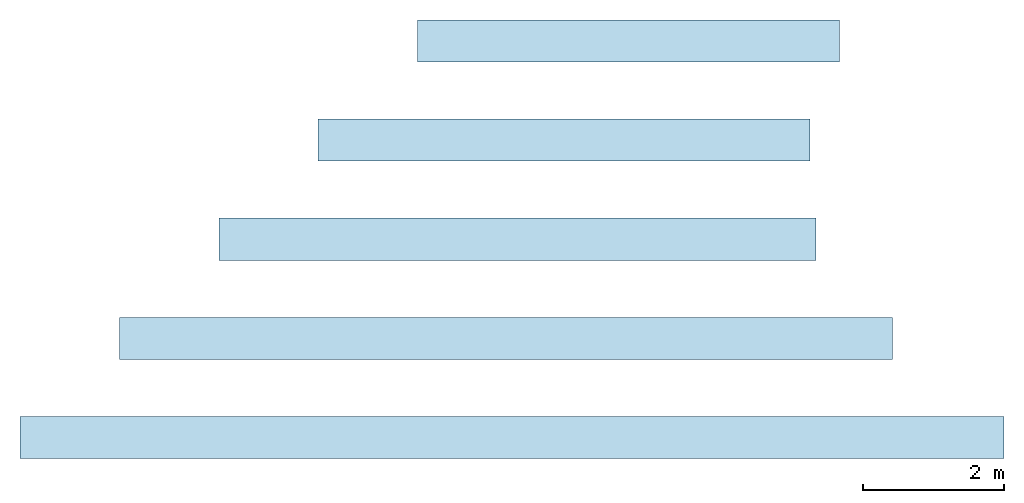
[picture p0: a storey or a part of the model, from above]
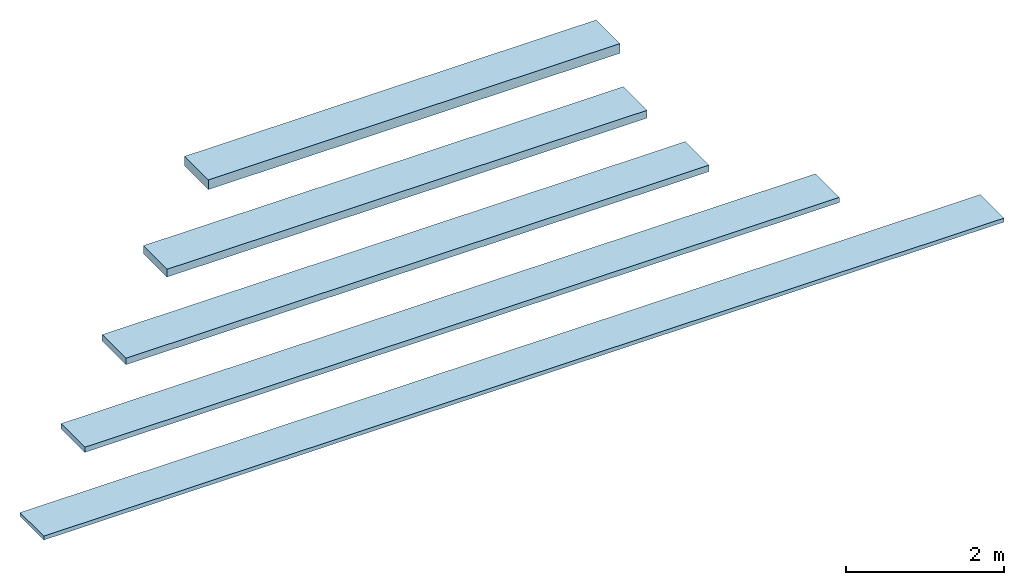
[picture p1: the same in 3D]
Properties of the parts of a building model (IFC2X3)

# File
Description: ViewDefinition [CoordinationView_V2.0, QuantityTakeOffAddOnView]
Time: 2021-05-19T20:20:11
Written by: The EXPRESS Data Manager Version 5.02.0100.07 : 28 Aug 2013
Made in: 20190108_1515(x64) - Exporter 19.1.0.0 - Alternate UI 19.1.0.0
Comment: STEP Physical File produced by: The EXPRESS Data Manager Version 5.02.0100.07 : 28 Aug 2013 * Module: EDMstepFileFactory/EDMstandAlone * Creation date: Wed May 19 20:20:11 2021 * Host: lt-026 * Database: C:\Users\WF2BF~1.POE\AppData\Local\Temp\{480D5C36-97AD-4BCC-B42C-12BA28B0F3CB}\ifc * Database version: 5507 * Database creation date: Wed May 19 20:20:10 2021 * Schema: IFC2X3 * Model: DataRepository.ifc * Model creation date: Wed May 19 20:20:10 2021 * Header model: DataRepository.ifc_HeaderModel * Header model creation date: Wed May 19 20:20:10 2021 * EDMuser: sdai-user * EDMgroup: sdai-group * License ID and type: 5605 : Permanent license. Expiry date: * EDMstepFileFactory options: 020000

# IfcSite, Default
RefLatitude: 42, 24, 53, 508911; RefLongitude: -71, -15, -29, -58837; RefElevation: 0 mm
Other - Category: Project Information

# IfcBuilding
Pset_BuildingCommon - NumberOfStoreys: 1
Pset_ProductRequirements - Category: Project Information; sets with these values: 2

# IfcBuildingStorey: Level:Level 1, Level 1
LongName: Level 1; Elevation: 0 mm
Pset_AirSideSystemInformation - Name: Level 1
Pset_ProductRequirements - Name: Level 1; Category: Levels
Constraints - Elevation: 0 mm
Dimensions - Computation Height: 0 mm
Identity Data - Building Story: yes; Name: Level 1; Structural: no
Other - Category: Levels; Family: Level: Level 1; Family and Type: Level: Level 1; Type: Level: Level 1; Type Id: Level: Level 1
Constraints(Type) - Elevation Base: Project Base Point
Graphics(Type) - Color: 0; Line Pattern: Solid; Line Weight: 1; Symbol at End 1 Default: no; Symbol at End 2 Default: yes
Identity Data(Type) - Type Name: Level 1
Other(Type) - Category: Levels; Family Name: Level

# IfcRoof: Basic Roof:NLRS_27_RO_TR 312_100x600x8500mm, Basic Roof:NLRS_27_RO_TR 312_100x600x8500mm:2467
In: Level 1
Classification: 27 Daken (Uniformat)
Pset_ElementShading - Roughness: 304.8 mm
Pset_ManufacturerTypeInformation - Manufacturer: Knauf Insulation B.V.
Pset_ProductRequirements - Category: Roofs
Pset_QuantityTakeOff - Reference: NLRS_27_RO_TR 312_100x600x8500mm
Pset_RoofCommon - IsExternal: yes; Reference: NLRS_27_RO_TR 312_100x600x8500mm; ProjectedArea: 5.1 m2; TotalArea: 5.1 m2
Constraints - Base Level: Level: Level 1; Base Offset From Level: 0 mm; Cutoff Offset: 0 mm; Related to Mass: no; Room Bounding: yes
Construction - Fascia Depth: 0 mm; Rafter Cut: Plumb Cut; Maximum Ridge Height: 100 mm
Dimensions - Area: 5.1 m2; Thickness: 100 mm; Volume: 0.51 m3
Other - Category: Roofs; Family: Basic Roof: NLRS_27_RO_TR 312_100x600x8500mm; Family and Type: Basic Roof: NLRS_27_RO_TR 312_100x600x8500mm; Type: Basic Roof: NLRS_27_RO_TR 312_100x600x8500mm; Type Id: Basic Roof: NLRS_27_RO_TR 312_100x600x8500mm
Phasing - Phase Created: New Construction
Analytical Properties(Type) - Roughness: 1; Thermal mass: 0; Absorptance: 0.1; Heat Transfer Coefficient (U): 0.4; Thermal Resistance (R): 2.5
Construction(Type) - Default Thickness: 100 mm
Graphics(Type) - Coarse Scale Fill Color: 0
Identity Data(Type) - Type Image: Raster image: TR 312 .jpg (2); Assembly Code: 27; Assembly Description: Daken; Description: TR 312 - 100mm; Manufacturer: Knauf Insulation B.V.; Model: TR312 is een glaswoldeken met alukraftbkleding en ECOSE® Technology; Type Name: NLRS_27_RO_TR 312_100x600x8500mm; URL: www.knaufinsulation.nl
Other(Type) - Category: Roofs; Family Name: Basic Roof

# IfcRoof: Basic Roof:NLRS_27_RO_TR 312_120x600x7000mm, Basic Roof:NLRS_27_RO_TR 312_120x600x7000mm:2476
In: Level 1
Classification: 27 Daken (Uniformat)
Pset_ElementShading - Roughness: 304.8 mm
Pset_ManufacturerTypeInformation - Manufacturer: Knauf Insulation B.V.
Pset_ProductRequirements - Category: Roofs
Pset_QuantityTakeOff - Reference: NLRS_27_RO_TR 312_120x600x7000mm
Pset_RoofCommon - IsExternal: yes; Reference: NLRS_27_RO_TR 312_120x600x7000mm; ProjectedArea: 4.2 m2; TotalArea: 4.2 m2
Constraints - Base Level: Level: Level 1; Base Offset From Level: 0 mm; Cutoff Offset: 0 mm; Related to Mass: no; Room Bounding: yes
Construction - Fascia Depth: 0 mm; Rafter Cut: Plumb Cut; Maximum Ridge Height: 120 mm
Dimensions - Area: 4.2 m2; Thickness: 120 mm; Volume: 0.504 m3
Other - Category: Roofs; Family: Basic Roof: NLRS_27_RO_TR 312_120x600x7000mm; Family and Type: Basic Roof: NLRS_27_RO_TR 312_120x600x7000mm; Type: Basic Roof: NLRS_27_RO_TR 312_120x600x7000mm; Type Id: Basic Roof: NLRS_27_RO_TR 312_120x600x7000mm
Phasing - Phase Created: New Construction
Analytical Properties(Type) - Roughness: 1; Thermal mass: 0; Absorptance: 0.1; Heat Transfer Coefficient (U): 0.333333; Thermal Resistance (R): 3
Construction(Type) - Default Thickness: 120 mm
Graphics(Type) - Coarse Scale Fill Color: 0
Identity Data(Type) - Type Image: Raster image: TR 312 .jpg (2); Assembly Code: 27; Assembly Description: Daken; Description: TR 312 - 120mm; Manufacturer: Knauf Insulation B.V.; Model: TR312 is een glaswoldeken met alukraftbkleding en ECOSE® Technology; Type Name: NLRS_27_RO_TR 312_120x600x7000mm; URL: www.knaufinsulation.nl
Other(Type) - Category: Roofs; Family Name: Basic Roof

# IfcRoof: Basic Roof:NLRS_27_RO_TR 312_150X600X6000mm, Basic Roof:NLRS_27_RO_TR 312_150X600X6000mm:2485
In: Level 1
Classification: 27 Daken (Uniformat)
Pset_ElementShading - Roughness: 304.8 mm
Pset_ManufacturerTypeInformation - Manufacturer: Knauf Insulation B.V.
Pset_ProductRequirements - Category: Roofs
Pset_QuantityTakeOff - Reference: NLRS_27_RO_TR 312_150X600X6000mm
Pset_RoofCommon - IsExternal: yes; Reference: NLRS_27_RO_TR 312_150X600X6000mm; ProjectedArea: 3.6 m2; TotalArea: 3.6 m2
Constraints - Base Level: Level: Level 1; Base Offset From Level: 0 mm; Cutoff Offset: 0 mm; Related to Mass: no; Room Bounding: yes
Construction - Fascia Depth: 0 mm; Rafter Cut: Plumb Cut; Maximum Ridge Height: 150 mm
Dimensions - Area: 3.6 m2; Thickness: 150 mm; Volume: 0.54 m3
Other - Category: Roofs; Family: Basic Roof: NLRS_27_RO_TR 312_150X600X6000mm; Family and Type: Basic Roof: NLRS_27_RO_TR 312_150X600X6000mm; Type: Basic Roof: NLRS_27_RO_TR 312_150X600X6000mm; Type Id: Basic Roof: NLRS_27_RO_TR 312_150X600X6000mm
Phasing - Phase Created: New Construction
Analytical Properties(Type) - Roughness: 1; Thermal mass: 0; Absorptance: 0.1; Heat Transfer Coefficient (U): 0.266667; Thermal Resistance (R): 3.75
Construction(Type) - Default Thickness: 150 mm
Graphics(Type) - Coarse Scale Fill Color: 0
Identity Data(Type) - Type Image: Raster image: TR 312 .jpg (2); Assembly Code: 27; Assembly Description: Daken; Description: TR 312 - 150mm; Manufacturer: Knauf Insulation B.V.; Model: TR312 is een glaswoldeken met alukraftbkleding en ECOSE® Technology; Type Name: NLRS_27_RO_TR 312_150X600X6000mm; URL: www.knaufinsulation.nl
Other(Type) - Category: Roofs; Family Name: Basic Roof

# IfcRoof: Basic Roof:NLRS_27_RO_TR 312_60x600x14000mm, Basic Roof:NLRS_27_RO_TR 312_60x600x14000mm:2449
In: Level 1
Classification: 27 Daken (Uniformat)
Pset_ElementShading - Roughness: 304.8 mm
Pset_ManufacturerTypeInformation - Manufacturer: Knauf Insulation B.V.
Pset_ProductRequirements - Category: Roofs
Pset_QuantityTakeOff - Reference: NLRS_27_RO_TR 312_60x600x14000mm
Pset_RoofCommon - Reference: NLRS_27_RO_TR 312_60x600x14000mm; IsExternal: yes; ProjectedArea: 8.4 m2; TotalArea: 8.4 m2
Constraints - Base Level: Level: Level 1; Base Offset From Level: 0 mm; Cutoff Offset: 0 mm; Related to Mass: no; Room Bounding: yes
Construction - Fascia Depth: 0 mm; Maximum Ridge Height: 60 mm; Rafter Cut: Plumb Cut
Dimensions - Area: 8.4 m2; Thickness: 60 mm; Volume: 0.504 m3
Other - Category: Roofs; Family: Basic Roof: NLRS_27_RO_TR 312_60x600x14000mm; Family and Type: Basic Roof: NLRS_27_RO_TR 312_60x600x14000mm; Type: Basic Roof: NLRS_27_RO_TR 312_60x600x14000mm; Type Id: Basic Roof: NLRS_27_RO_TR 312_60x600x14000mm
Phasing - Phase Created: New Construction
Analytical Properties(Type) - Absorptance: 0.1; Heat Transfer Coefficient (U): 0.666667; Roughness: 1; Thermal mass: 0; Thermal Resistance (R): 1.5
Construction(Type) - Default Thickness: 60 mm
Graphics(Type) - Coarse Scale Fill Color: 0
Identity Data(Type) - Assembly Code: 27; Assembly Description: Daken; Description: TR 312 - 60mm; Manufacturer: Knauf Insulation B.V.; Model: TR312 is een glaswoldeken met alukraftbkleding en ECOSE® Technology; Type Image: Raster image: TR 312 .jpg (2); Type Name: NLRS_27_RO_TR 312_60x600x14000mm; URL: www.knaufinsulation.nl
Other(Type) - Category: Roofs; Family Name: Basic Roof

# IfcRoof: Basic Roof:NLRS_27_RO_TR 312_80x600x11000mm, Basic Roof:NLRS_27_RO_TR 312_80x600x11000mm:2458
In: Level 1
Classification: 27 Daken (Uniformat)
Pset_ElementShading - Roughness: 304.8 mm
Pset_ManufacturerTypeInformation - Manufacturer: Knauf Insulation B.V.
Pset_ProductRequirements - Category: Roofs
Pset_QuantityTakeOff - Reference: NLRS_27_RO_TR 312_80x600x11000mm
Pset_RoofCommon - IsExternal: yes; Reference: NLRS_27_RO_TR 312_80x600x11000mm; ProjectedArea: 6.6 m2; TotalArea: 6.6 m2
Constraints - Base Level: Level: Level 1; Base Offset From Level: 0 mm; Cutoff Offset: 0 mm; Related to Mass: no; Room Bounding: yes
Construction - Fascia Depth: 0 mm; Rafter Cut: Plumb Cut; Maximum Ridge Height: 80 mm
Dimensions - Area: 6.6 m2; Thickness: 80 mm; Volume: 0.528 m3
Other - Category: Roofs; Family: Basic Roof: NLRS_27_RO_TR 312_80x600x11000mm; Family and Type: Basic Roof: NLRS_27_RO_TR 312_80x600x11000mm; Type: Basic Roof: NLRS_27_RO_TR 312_80x600x11000mm; Type Id: Basic Roof: NLRS_27_RO_TR 312_80x600x11000mm
Phasing - Phase Created: New Construction
Analytical Properties(Type) - Roughness: 1; Thermal mass: 0; Absorptance: 0.1; Heat Transfer Coefficient (U): 0.5; Thermal Resistance (R): 2
Construction(Type) - Default Thickness: 80 mm
Graphics(Type) - Coarse Scale Fill Color: 0
Identity Data(Type) - Type Image: Raster image: TR 312 .jpg (2); Assembly Code: 27; Assembly Description: Daken; Description: TR 312 - 80mm; Manufacturer: Knauf Insulation B.V.; Model: TR312 is een glaswoldeken met alukraftbkleding en ECOSE® Technology; Type Name: NLRS_27_RO_TR 312_80x600x11000mm; URL: www.knaufinsulation.nl
Other(Type) - Category: Roofs; Family Name: Basic Roof

# IfcSlab: Basic Roof:NLRS_27_RO_TR 312_100x600x8500mm, Basic Roof:NLRS_27_RO_TR 312_100x600x8500mm:2467
In: Level 1
PredefinedType: ROOF; Classification: 27 Daken (Uniformat); Material: Knauf Insulation_Ecose® glaswol TR 312 100 mm
Pset_ElementShading - Roughness: 304.8 mm
Pset_ManufacturerTypeInformation - Manufacturer: Knauf Insulation B.V.
Pset_ProductRequirements - Category: Roofs
Pset_QuantityTakeOff - Reference: NLRS_27_RO_TR 312_100x600x8500mm
Pset_ReinforcementBarPitchOfSlab - Description: TR 312 - 100mm; Reference: NLRS_27_RO_TR 312_100x600x8500mm
Pset_SlabCommon - IsExternal: yes; PitchAngle: 0 deg; Reference: NLRS_27_RO_TR 312_100x600x8500mm; ThermalTransmittance: 0.4 kg/K/s3
BaseQuantities - GrossArea: 0.473806 m2; NetArea: 12.02 m2; GrossVolume: 47.3806 m3; NetVolume: 0.51 m3; Perimeter: 18200 mm; Width: 100 mm

# IfcSlab: Basic Roof:NLRS_27_RO_TR 312_120x600x7000mm, Basic Roof:NLRS_27_RO_TR 312_120x600x7000mm:2476
In: Level 1
PredefinedType: ROOF; Classification: 27 Daken (Uniformat); Material: Knauf Insulation_Ecose® glaswol TR 312 120 mm
Pset_ElementShading - Roughness: 304.8 mm
Pset_ManufacturerTypeInformation - Manufacturer: Knauf Insulation B.V.
Pset_ProductRequirements - Category: Roofs
Pset_QuantityTakeOff - Reference: NLRS_27_RO_TR 312_120x600x7000mm
Pset_ReinforcementBarPitchOfSlab - Description: TR 312 - 120mm; Reference: NLRS_27_RO_TR 312_120x600x7000mm
Pset_SlabCommon - IsExternal: yes; PitchAngle: 0 deg; Reference: NLRS_27_RO_TR 312_120x600x7000mm; ThermalTransmittance: 0.333333 kg/K/s3
BaseQuantities - GrossArea: 0.390193 m2; NetArea: 10.224 m2; GrossVolume: 46.8231 m3; NetVolume: 0.504 m3; Perimeter: 15200 mm; Width: 120 mm

# IfcSlab: Basic Roof:NLRS_27_RO_TR 312_150X600X6000mm, Basic Roof:NLRS_27_RO_TR 312_150X600X6000mm:2485
In: Level 1
PredefinedType: ROOF; Classification: 27 Daken (Uniformat); Material: Knauf Insulation_Ecose® glaswol TR 312 150 mm
Pset_ElementShading - Roughness: 304.8 mm
Pset_ManufacturerTypeInformation - Manufacturer: Knauf Insulation B.V.
Pset_ProductRequirements - Category: Roofs
Pset_QuantityTakeOff - Reference: NLRS_27_RO_TR 312_150X600X6000mm
Pset_ReinforcementBarPitchOfSlab - Description: TR 312 - 150mm; Reference: NLRS_27_RO_TR 312_150X600X6000mm
Pset_SlabCommon - IsExternal: yes; PitchAngle: 0 deg; Reference: NLRS_27_RO_TR 312_150X600X6000mm; ThermalTransmittance: 0.266667 kg/K/s3
BaseQuantities - GrossArea: 0.334451 m2; NetArea: 9.18 m2; GrossVolume: 50.1676 m3; NetVolume: 0.54 m3; Perimeter: 13200 mm; Width: 150 mm

# IfcSlab: Basic Roof:NLRS_27_RO_TR 312_60x600x14000mm, Basic Roof:NLRS_27_RO_TR 312_60x600x14000mm:2449
In: Level 1
PredefinedType: ROOF; Classification: 27 Daken (Uniformat); Material: Knauf Insulation_Ecose® glaswol TR 312 60 mm
Pset_ElementShading - Roughness: 304.8 mm
Pset_ManufacturerTypeInformation - Manufacturer: Knauf Insulation B.V.
Pset_ProductRequirements - Category: Roofs
Pset_QuantityTakeOff - Reference: NLRS_27_RO_TR 312_60x600x14000mm
Pset_ReinforcementBarPitchOfSlab - Description: TR 312 - 60mm; Reference: NLRS_27_RO_TR 312_60x600x14000mm
Pset_SlabCommon - Reference: NLRS_27_RO_TR 312_60x600x14000mm; IsExternal: yes; ThermalTransmittance: 0.666667 kg/K/s3; PitchAngle: 0 deg
BaseQuantities - GrossArea: 0.780386 m2; NetArea: 18.552 m2; GrossVolume: 46.8231 m3; NetVolume: 0.504 m3; Perimeter: 29200 mm; Width: 60 mm

# IfcSlab: Basic Roof:NLRS_27_RO_TR 312_80x600x11000mm, Basic Roof:NLRS_27_RO_TR 312_80x600x11000mm:2458
In: Level 1
PredefinedType: ROOF; Classification: 27 Daken (Uniformat); Material: Knauf Insulation_Ecose® glaswol TR 312 80 mm
Pset_ElementShading - Roughness: 304.8 mm
Pset_ManufacturerTypeInformation - Manufacturer: Knauf Insulation B.V.
Pset_ProductRequirements - Category: Roofs
Pset_QuantityTakeOff - Reference: NLRS_27_RO_TR 312_80x600x11000mm
Pset_ReinforcementBarPitchOfSlab - Description: TR 312 - 80mm; Reference: NLRS_27_RO_TR 312_80x600x11000mm
Pset_SlabCommon - IsExternal: yes; PitchAngle: 0 deg; Reference: NLRS_27_RO_TR 312_80x600x11000mm; ThermalTransmittance: 0.5 kg/K/s3
BaseQuantities - GrossArea: 0.61316 m2; NetArea: 15.056 m2; GrossVolume: 49.0528 m3; NetVolume: 0.528 m3; Perimeter: 23200 mm; Width: 80 mm
